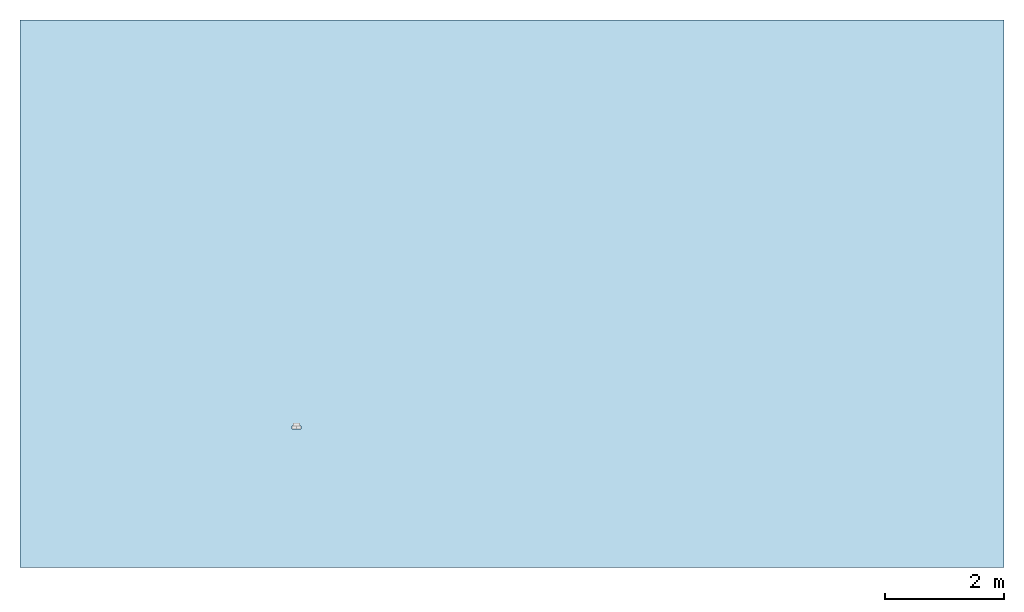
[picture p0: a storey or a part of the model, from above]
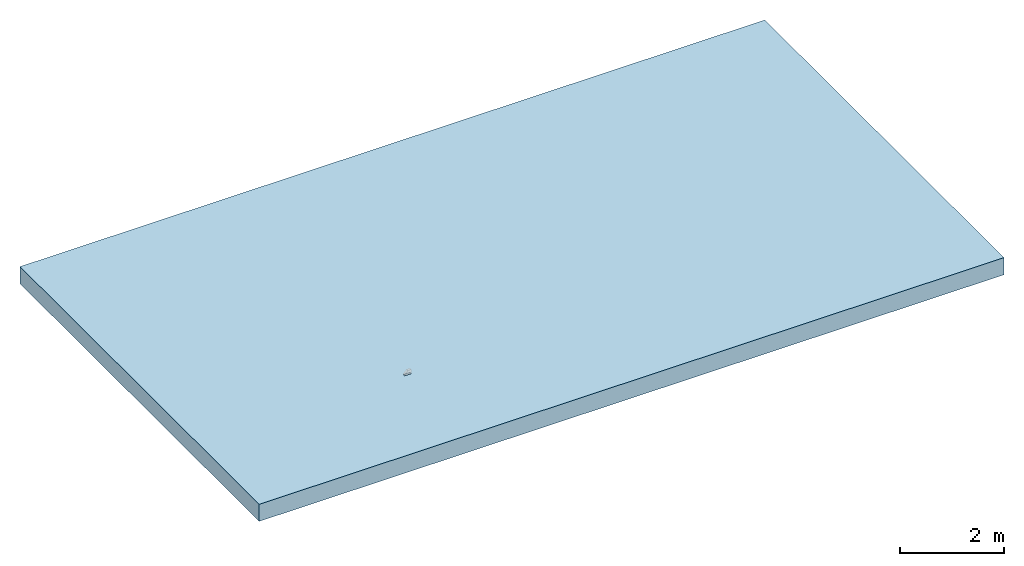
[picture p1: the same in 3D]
Properties of the parts of a building model (IFC2X3)

# File
Description: ViewDefinition [CoordinationView]
File name: 4248 - RH inlet-outlet end cap.ifc
Time: 2013-09-02T12:25:03
Written by: Autodesk Revit 2013
Made in: 20120221_2030(x64)

# IfcProject, Project Number
LongName: Project Name; Phase: Project Status

# IfcSite, Default
RefLatitude: 42, 21, 30, 344238; RefLongitude: -71, -3, -35, -194702; RefElevation: 0 mm

# IfcBuilding
Pset_BuildingCommon - NumberOfStoreys: 1
Other - Project Address: ## Street City, State Zip; Client Name: Owner; Project Name: Project Name; Project Issue Date: Issue Date; Project Number: Project Number; Project Status: Project Status

# IfcBuildingStorey, Level 1
LongName: Level 1; Elevation: 0 mm
Graphics - Symbol: M_Level Head - Circle: M_Level Head - Circle; Symbol at End 2 Default: yes; Line Weight: 1; Symbol at End 1 Default: no; Line Pattern: Center; Color: 0
Constraints - Elevation Base: 0; Elevation: 0 mm
Identity Data - Structural: no; Building Story: yes; Name: Level 1
Dimensions - Computation Height: 0 mm

# IfcBuildingElementProxy: 4248 - RH inlet/outlet end cap, Civil-Drainage-Channel-ACO-KerbDrain-SP380:4248 - RH inlet/outlet end cap:4248 - RH inlet/outlet end cap:308659
In: Level 1
Material: Orange, ACO Polymer Concrete.
Other - CreatedBy: www.aco.co.uk; Revision: 1
Constraints - Level: Level: Level 1; Moves With Nearby Elements: no
Phasing - Phase Created: New Construction
Dimensions - Volume: 2398369 mm3; Endcap void: 329.992 mm; Void Length: 50 mm; Void Width: 150 mm; Access hole: 2 mm; AccessDepth: 2000 mm; Void Depth: -280 mm
Pset_BuildingElementProxyCommon - Reference: 4248 - RH inlet/outlet end cap
Data - ACO Hydraulic Design Software: N/A; Drainage Slot Width: N/A; Connection Pipe O.D: Ø110mm; Concrete Surround Volume - Load Class A 15 - D 400 - Concrete Pavement: N/A; Product Dimensions: 50mm x 150mm x 380mm (LxWxH); Invert Depth: N/A; Drainage Slot Intake area: N/A; Product Weight: 5.1 Kg; Hydraulic Performance: N/A; Installation - Concrete Grade: N/A; Channel C.S.A: N/A; Load Class: N/A; Product Standard: N/A; Concrete Surround Volume - Load Class A 15 - D 400 - Grass or Asphalt Pavement: N/A
General - SerialNumber: 0.000000; TagNumber: 0.000000
Materials and Finishes - Channel Material: N/A; Connection Pipe Material Colour: Brown; Channel Colour: N/A; Access Cover/Frame Colour: N/A; Access Cover/Frame Material: N/A; End Cap Colour: Grey; Connection Pipe Material: PVCu; Access Cover/Frame Finish: N/A; End Cap Material: Vienite® Synthetic Resin Concrete
Identity Data - Product Code: 4248; Assembly Description: Rain Water Drainage; e-mail Sales: customersupport@aco.co.uk; OmniClass Title: Rainwater Removal; Model: ACO KerbDrain SP380; Type Comments: ACO KerbDrain SP380 splayed RH inlet / outlet end cap; Maintenance guidelines: http://www.aco.co.uk/download.php?id=120; e-mail Technical: technical@aco.co.uk; Telephone: +44 (0)1462 816666; Product Page URL: http://www.aco.co.uk/product_detail.php?id=3; Manufacturer: ACO Technologies plc - ACO Water Management Division; Model Description: Combined kerb and drainage system; Installation guidelines: http://www.aco.co.uk/download.php?id=120; Product brochure: http://www.aco.co.uk/download.php?id=120; Fax: +44 (0)1462 815895; OmniClass Number: 23.70.50.24; URL: www.aco.co.uk; Price: POA - contact ACO; Assembly Code: D2040; Address: ACO Business Park, Hitchin Road, Shefford, Bedfordshire, United Kingdom SG17 5TE; Cost: 0
Green Building Properties - Access Cover/Frame Recyclable: N/A; End Cap Recycled Material Content: 20% minimum; Access Cover/Frame Recycled Material Content: N/A; End Cap Recyclable: Fully recyclable; Channel Recyclable: N/A; Channel Recycled Material Content: N/A
Construction - LH inlet/outlet end cap: no; SP380-500: no; Closing end cap: no; Access Unit: no; SP380 - 1000: no; RH drop kerb: no; LH transition unit: no; RH inlet/outlet end cap: yes; RH transition unit: no; Centre Stone: no; LH drop kerb: no

# IfcOpeningElement: Recess (2)
In: Level 1
Dimensions - Volume: 60585431385 mm3; Area: 151470000 mm2; Perimeter: 51360 mm; Thickness: 400 mm
Structural - Enable Analytical Model: no; Structural: no
Phasing - Phase Created: New Construction
Constraints - Height Offset From Level: 0 mm; Related to Mass: no; Level: Level: Level 1; Room Bounding: yes
Construction - Default Thickness: 400 mm; Function: 0
Analytical Properties - Roughness: 1; Absorptance: 0.1
Materials and Finishes - Structural Material: Plant
Graphics - Coarse Scale Fill Color: 0

# IfcSlab: Floor:Generic Floor - 400mm, Floor:Generic Floor - 400mm:193825
In: Level 1
PredefinedType: FLOOR; Material: Plant 400 mm
Dimensions - Volume: 60585431385 mm3; Area: 151470000 mm2; Perimeter: 51360 mm; Thickness: 400 mm
Structural - Enable Analytical Model: no; Structural: no
Phasing - Phase Created: New Construction
Constraints - Height Offset From Level: 0 mm; Related to Mass: no; Level: Level: Level 1; Room Bounding: yes
Pset_SlabCommon - Reference: Generic Floor - 400mm; IsExternal: no; LoadBearing: yes
Construction - Default Thickness: 400 mm; Function: 0
Analytical Properties - Roughness: 1; Absorptance: 0.1
Materials and Finishes - Structural Material: Plant
Graphics - Coarse Scale Fill Color: 0
